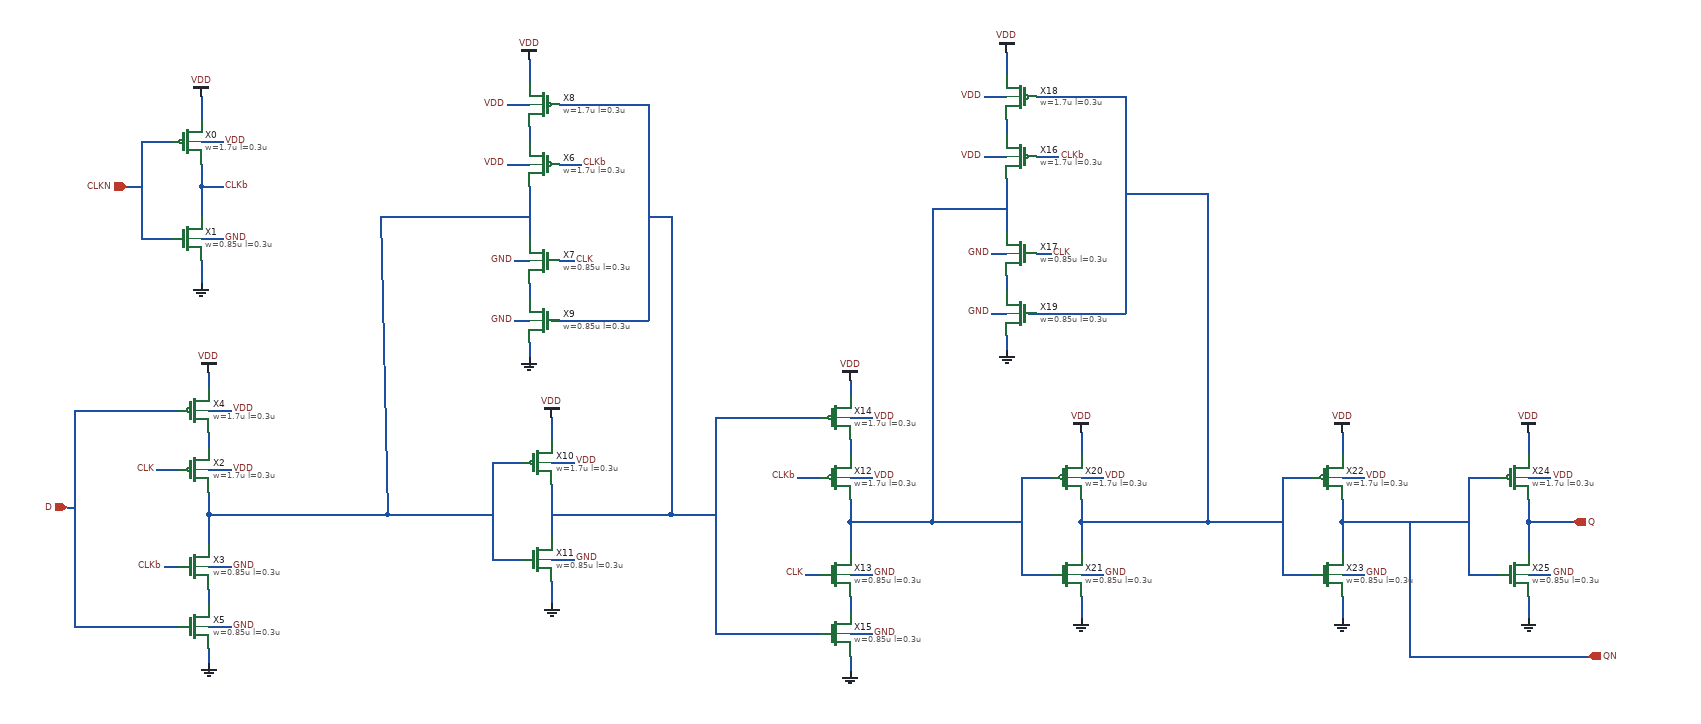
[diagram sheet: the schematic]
v {xschem version=3.0.0 file_version=1.2 }
G {}
K {}
V {}
S {}
E {}
N 260 -800 260 -770 { lab=VDD}
N 260 -710 260 -680 { lab=CLKb}
N 260 -680 260 -640 { lab=CLKb}
N 260 -580 260 -550 { lab=GND}
N 200 -740 220 -740 { lab=CLK}
N 180 -740 180 -610 { lab=CLK}
N 160 -680 180 -680 { lab=CLK}
N 180 -740 200 -740 { lab=CLK}
N 180 -610 220 -610 { lab=CLK}
N 260 -740 290 -740 { lab=VDD}
N 260 -610 290 -610 { lab=GND}
N 260 -680 290 -680 { lab=CLKb}
N 270 -270 270 -240 { lab=#net1}
N 270 -240 270 -200 { lab=#net1}
N 270 -300 300 -300 { lab=VDD}
N 270 -170 300 -170 { lab=GND}
N 270 -240 300 -240 { lab=#net1}
N 210 -380 230 -380 { lab=D}
N 270 -380 300 -380 { lab=VDD}
N 270 -350 270 -330 { lab=#net2}
N 270 -60 270 -30 { lab=GND}
N 270 -90 300 -90 { lab=GND}
N 270 -140 270 -120 { lab=#net3}
N 270 -430 270 -400 { lab=VDD}
N 90 -90 230 -90 { lab=D}
N 90 -380 90 -90 { lab=D}
N 90 -380 210 -380 { lab=D}
N 80 -250 90 -250 { lab=D}
N 700 -470 700 -440 { lab=GND}
N 700 -850 700 -820 { lab=VDD}
N 700 -760 700 -740 { lab=#net4}
N 700 -550 700 -530 { lab=#net5}
N 700 -680 700 -610 { lab=#net1}
N 670 -790 700 -790 { lab=VDD}
N 670 -710 700 -710 { lab=VDD}
N 680 -500 700 -500 { lab=GND}
N 680 -580 700 -580 { lab=GND}
N 730 -500 860 -500 { lab=#net6}
N 740 -790 860 -790 { lab=#net6}
N 860 -790 860 -500 { lab=#net6}
N 740 -710 770 -710 { lab=CLKb}
N 740 -580 760 -580 { lab=CLK}
N 300 -240 510 -240 { lab=#net1}
N 500 -640 510 -240 { lab=#net1}
N 500 -640 700 -640 { lab=#net1}
N 730 -370 730 -340 { lab=VDD}
N 730 -280 730 -250 { lab=#net6}
N 730 -250 730 -210 { lab=#net6}
N 730 -150 730 -120 { lab=GND}
N 670 -310 690 -310 { lab=#net1}
N 650 -310 650 -180 { lab=#net1}
N 650 -310 670 -310 { lab=#net1}
N 650 -180 690 -180 { lab=#net1}
N 730 -310 760 -310 { lab=VDD}
N 730 -180 760 -180 { lab=GND}
N 510 -240 650 -240 { lab=#net1}
N 730 -240 890 -240 { lab=#net6}
N 890 -640 890 -240 { lab=#net6}
N 860 -640 890 -640 { lab=#net6}
N 1130 -260 1130 -230 { lab=#net7}
N 1130 -230 1130 -190 { lab=#net7}
N 1130 -290 1160 -290 { lab=VDD}
N 1130 -160 1160 -160 { lab=GND}
N 1130 -230 1160 -230 { lab=#net7}
N 1070 -370 1090 -370 { lab=#net6}
N 1130 -370 1160 -370 { lab=VDD}
N 1130 -340 1130 -320 { lab=#net8}
N 1130 -50 1130 -20 { lab=GND}
N 1130 -80 1160 -80 { lab=GND}
N 1130 -130 1130 -110 { lab=#net9}
N 1130 -420 1130 -390 { lab=VDD}
N 950 -80 1090 -80 { lab=#net6}
N 950 -370 950 -80 { lab=#net6}
N 950 -370 1070 -370 { lab=#net6}
N 890 -240 950 -240 { lab=#net6}
N 1340 -480 1340 -450 { lab=GND}
N 1340 -860 1340 -830 { lab=VDD}
N 1340 -770 1340 -750 { lab=#net10}
N 1340 -560 1340 -540 { lab=#net11}
N 1340 -690 1340 -620 { lab=#net7}
N 1310 -800 1340 -800 { lab=VDD}
N 1310 -720 1340 -720 { lab=VDD}
N 1320 -510 1340 -510 { lab=GND}
N 1320 -590 1340 -590 { lab=GND}
N 1370 -510 1500 -510 { lab=#net12}
N 1380 -800 1500 -800 { lab=#net12}
N 1500 -800 1500 -510 { lab=#net12}
N 1380 -720 1410 -720 { lab=CLKb}
N 1380 -590 1400 -590 { lab=CLK}
N 1160 -230 1240 -230 { lab=#net7}
N 1240 -650 1240 -230 { lab=#net7}
N 1240 -650 1340 -650 { lab=#net7}
N 1440 -350 1440 -320 { lab=VDD}
N 1440 -260 1440 -230 { lab=#net12}
N 1440 -230 1440 -190 { lab=#net12}
N 1440 -130 1440 -100 { lab=GND}
N 1380 -290 1400 -290 { lab=#net7}
N 1360 -290 1360 -160 { lab=#net7}
N 1360 -290 1380 -290 { lab=#net7}
N 1360 -160 1400 -160 { lab=#net7}
N 1440 -290 1470 -290 { lab=VDD}
N 1440 -160 1470 -160 { lab=GND}
N 1240 -230 1360 -230 { lab=#net7}
N 1440 -230 1610 -230 { lab=#net12}
N 1610 -670 1610 -230 { lab=#net12}
N 1500 -670 1610 -670 { lab=#net12}
N 1790 -350 1790 -320 { lab=VDD}
N 1790 -260 1790 -230 { lab=QN}
N 1790 -230 1790 -190 { lab=QN}
N 1790 -130 1790 -100 { lab=GND}
N 1730 -290 1750 -290 { lab=#net12}
N 1710 -290 1710 -160 { lab=#net12}
N 1710 -290 1730 -290 { lab=#net12}
N 1710 -160 1750 -160 { lab=#net12}
N 1790 -290 1820 -290 { lab=VDD}
N 1790 -160 1820 -160 { lab=GND}
N 2040 -350 2040 -320 { lab=VDD}
N 2040 -260 2040 -230 { lab=Q}
N 2040 -230 2040 -190 { lab=Q}
N 2040 -130 2040 -100 { lab=GND}
N 1980 -290 2000 -290 { lab=QN}
N 1960 -290 1960 -160 { lab=QN}
N 1960 -290 1980 -290 { lab=QN}
N 1960 -160 2000 -160 { lab=QN}
N 2040 -290 2070 -290 { lab=VDD}
N 2040 -160 2070 -160 { lab=GND}
N 1610 -230 1710 -230 { lab=#net12}
N 1790 -230 1960 -230 { lab=QN}
N 2040 -230 2100 -230 { lab=Q}
N 1880 -230 1880 -50 { lab=QN}
N 1880 -50 2120 -50 { lab=QN}
N 210 -170 230 -170 { lab=CLKb}
N 1070 -160 1090 -160 { lab=CLK}
N 200 -300 230 -300 { lab=CLK}
N 1060 -290 1090 -290 { lab=CLKb}
C {vdd.sym} 260 -800 0 0 {name=l1 lab=VDD}
C {gnd.sym} 260 -550 0 0 {name=l3 lab=GND}
C {ipin.sym} 160 -680 0 0 {name=p3 lab=CLKN
}
C {pmos4.sym} 240 -740 0 0 {name=X0 model=pmos_3p3 w=1.7u l=0.3u m=1}
C {nmos4.sym} 240 -610 0 0 {name=X1 model=nmos_3p3 w=0.85u l=0.3u m=1}
C {lab_wire.sym} 290 -740 2 0 {name=l2 sig_type=std_logic lab=VDD
}
C {lab_wire.sym} 290 -610 2 0 {name=l4 sig_type=std_logic lab=GND
}
C {lab_wire.sym} 290 -680 2 0 {name=l5 sig_type=std_logic lab=CLKb}
C {pmos4.sym} 250 -300 0 0 {name=X2 model=pmos_3p3 w=1.7u l=0.3u m=1}
C {nmos4.sym} 250 -170 0 0 {name=X3 model=nmos_3p3 w=0.85u l=0.3u m=1}
C {lab_wire.sym} 300 -300 2 0 {name=l6 sig_type=std_logic lab=VDD
}
C {lab_wire.sym} 300 -170 2 0 {name=l7 sig_type=std_logic lab=GND
}
C {pmos4.sym} 250 -380 0 0 {name=X4 model=pmos_3p3 w=1.7u l=0.3u m=1}
C {lab_wire.sym} 300 -380 2 0 {name=l9 sig_type=std_logic lab=VDD
}
C {nmos4.sym} 250 -90 0 0 {name=X5 model=nmos_3p3 w=0.85u l=0.3u m=1}
C {lab_wire.sym} 300 -90 2 0 {name=l10 sig_type=std_logic lab=GND
}
C {gnd.sym} 270 -40 0 0 {name=l11 lab=GND}
C {vdd.sym} 270 -430 0 0 {name=l12 lab=VDD}
C {ipin.sym} 80 -250 0 0 {name=p1 lab=D
}
C {lab_wire.sym} 200 -300 0 0 {name=l13 sig_type=std_logic lab=CLK}
C {lab_wire.sym} 210 -170 0 0 {name=l14 sig_type=std_logic lab=CLKb}
C {pmos4.sym} 720 -710 0 1 {name=X6 model=pmos_3p3 w=1.7u l=0.3u m=1}
C {nmos4.sym} 720 -580 0 1 {name=X7 model=nmos_3p3 w=0.85u l=0.3u m=1}
C {lab_wire.sym} 670 -710 2 1 {name=l15 sig_type=std_logic lab=VDD
}
C {lab_wire.sym} 680 -580 2 1 {name=l16 sig_type=std_logic lab=GND
}
C {lab_wire.sym} 770 -710 0 1 {name=l17 sig_type=std_logic lab=CLKb}
C {pmos4.sym} 720 -790 0 1 {name=X8 model=pmos_3p3 w=1.7u l=0.3u m=1}
C {lab_wire.sym} 670 -790 2 1 {name=l18 sig_type=std_logic lab=VDD
}
C {nmos4.sym} 720 -500 0 1 {name=X9 model=nmos_3p3 w=0.85u l=0.3u m=1}
C {lab_wire.sym} 680 -500 2 1 {name=l19 sig_type=std_logic lab=GND
}
C {gnd.sym} 700 -450 0 1 {name=l20 lab=GND}
C {vdd.sym} 700 -850 0 1 {name=l21 lab=VDD}
C {lab_wire.sym} 760 -580 0 1 {name=l22 sig_type=std_logic lab=CLK}
C {vdd.sym} 730 -370 0 0 {name=l8 lab=VDD}
C {gnd.sym} 730 -120 0 0 {name=l23 lab=GND}
C {pmos4.sym} 710 -310 0 0 {name=X10 model=pmos_3p3 w=1.7u l=0.3u m=1}
C {nmos4.sym} 710 -180 0 0 {name=X11 model=nmos_3p3 w=0.85u l=0.3u m=1}
C {lab_wire.sym} 760 -310 2 0 {name=l24 sig_type=std_logic lab=VDD
}
C {lab_wire.sym} 760 -180 2 0 {name=l25 sig_type=std_logic lab=GND
}
C {pmos4.sym} 1110 -290 0 0 {name=X12 model=pmos_3p3 w=1.7u l=0.3u m=1}
C {nmos4.sym} 1110 -160 0 0 {name=X13 model=nmos_3p3 w=0.85u l=0.3u m=1}
C {lab_wire.sym} 1160 -290 2 0 {name=l26 sig_type=std_logic lab=VDD
}
C {lab_wire.sym} 1160 -160 2 0 {name=l27 sig_type=std_logic lab=GND
}
C {pmos4.sym} 1110 -370 0 0 {name=X14 model=pmos_3p3 w=1.7u l=0.3u m=1}
C {lab_wire.sym} 1160 -370 2 0 {name=l28 sig_type=std_logic lab=VDD
}
C {nmos4.sym} 1110 -80 0 0 {name=X15 model=nmos_3p3 w=0.85u l=0.3u m=1}
C {lab_wire.sym} 1160 -80 2 0 {name=l29 sig_type=std_logic lab=GND
}
C {gnd.sym} 1130 -30 0 0 {name=l30 lab=GND}
C {vdd.sym} 1130 -420 0 0 {name=l31 lab=VDD}
C {lab_wire.sym} 1060 -290 0 0 {name=l32 sig_type=std_logic lab=CLKb}
C {lab_wire.sym} 1070 -160 0 0 {name=l33 sig_type=std_logic lab=CLK}
C {pmos4.sym} 1360 -720 0 1 {name=X16 model=pmos_3p3 w=1.7u l=0.3u m=1}
C {nmos4.sym} 1360 -590 0 1 {name=X17 model=nmos_3p3 w=0.85u l=0.3u m=1}
C {lab_wire.sym} 1310 -720 2 1 {name=l34 sig_type=std_logic lab=VDD
}
C {lab_wire.sym} 1320 -590 2 1 {name=l35 sig_type=std_logic lab=GND
}
C {lab_wire.sym} 1410 -720 0 1 {name=l36 sig_type=std_logic lab=CLKb}
C {pmos4.sym} 1360 -800 0 1 {name=X18 model=pmos_3p3 w=1.7u l=0.3u m=1}
C {lab_wire.sym} 1310 -800 2 1 {name=l37 sig_type=std_logic lab=VDD
}
C {nmos4.sym} 1360 -510 0 1 {name=X19 model=nmos_3p3 w=0.85u l=0.3u m=1}
C {lab_wire.sym} 1320 -510 2 1 {name=l38 sig_type=std_logic lab=GND
}
C {gnd.sym} 1340 -460 0 1 {name=l39 lab=GND}
C {vdd.sym} 1340 -860 0 1 {name=l40 lab=VDD}
C {lab_wire.sym} 1400 -590 0 1 {name=l41 sig_type=std_logic lab=CLK}
C {vdd.sym} 1440 -350 0 0 {name=l42 lab=VDD}
C {gnd.sym} 1440 -100 0 0 {name=l43 lab=GND}
C {pmos4.sym} 1420 -290 0 0 {name=X20 model=pmos_3p3 w=1.7u l=0.3u m=2}
C {nmos4.sym} 1420 -160 0 0 {name=X21 model=nmos_3p3 w=0.85u l=0.3u m=2}
C {lab_wire.sym} 1470 -290 2 0 {name=l44 sig_type=std_logic lab=VDD
}
C {lab_wire.sym} 1470 -160 2 0 {name=l45 sig_type=std_logic lab=GND
}
C {vdd.sym} 1790 -350 0 0 {name=l46 lab=VDD}
C {gnd.sym} 1790 -100 0 0 {name=l47 lab=GND}
C {pmos4.sym} 1770 -290 0 0 {name=X22 model=pmos_3p3 w=1.7u l=0.3u m=1}
C {nmos4.sym} 1770 -160 0 0 {name=X23 model=nmos_3p3 w=0.85u l=0.3u m=1}
C {lab_wire.sym} 1820 -290 2 0 {name=l48 sig_type=std_logic lab=VDD
}
C {lab_wire.sym} 1820 -160 2 0 {name=l49 sig_type=std_logic lab=GND
}
C {vdd.sym} 2040 -350 0 0 {name=l50 lab=VDD}
C {gnd.sym} 2040 -100 0 0 {name=l51 lab=GND}
C {pmos4.sym} 2020 -290 0 0 {name=X24 model=pmos_3p3 w=1.7u l=0.3u m=1}
C {nmos4.sym} 2020 -160 0 0 {name=X25 model=nmos_3p3 w=0.85u l=0.3u m=1}
C {lab_wire.sym} 2070 -290 2 0 {name=l52 sig_type=std_logic lab=VDD
}
C {lab_wire.sym} 2070 -160 2 0 {name=l53 sig_type=std_logic lab=GND
}
C {opin.sym} 2100 -230 0 0 {name=p2 lab=Q}
C {opin.sym} 2120 -50 0 0 {name=p4 lab=QN}
